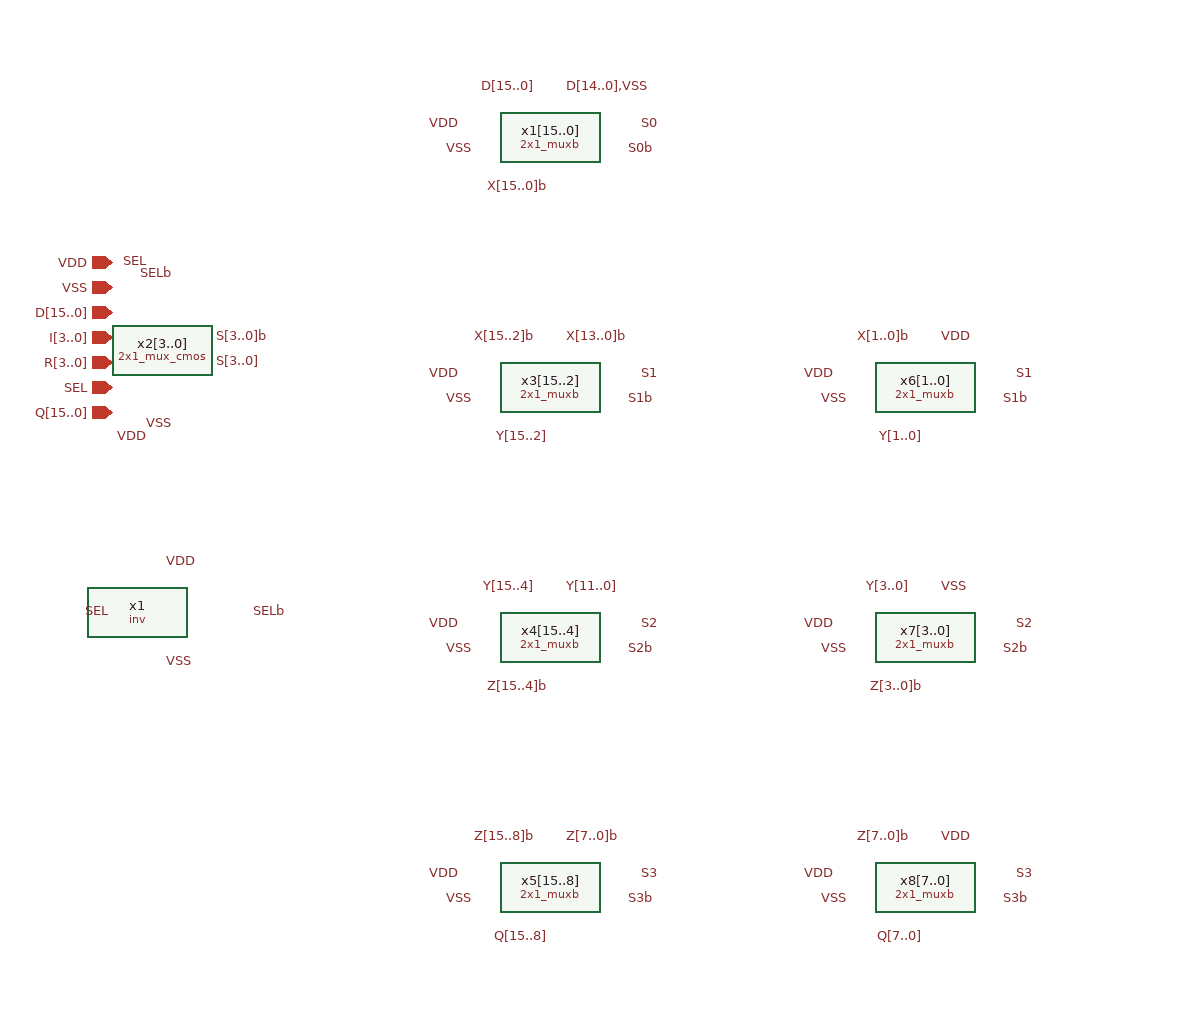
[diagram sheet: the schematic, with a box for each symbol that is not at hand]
v {xschem version=3.4.7 file_version=1.2}
G {}
K {}
V {}
S {}
E {}
C {engn1600-team1/CAD5/2x1_muxb.sym} 0 -300 3 1 {name=x1[15..0] kI=1 kYb=1 kY=1}
C {iopin.sym} -350 -200 2 0 {name=p1 lab=VDD}
C {iopin.sym} -350 -180 2 0 {name=p2 lab=VSS}
C {lab_pin.sym} -10 -340 2 1 {name=p3 lab=D[15..0]}
C {lab_pin.sym} 70 -310 0 1 {name=p4 lab=S0}
C {lab_pin.sym} 60 -290 0 1 {name=p5 lab=S0b}
C {lab_pin.sym} -70 -310 2 1 {name=p7 lab=VDD}
C {lab_pin.sym} -60 -290 0 0 {name=p8 lab=VSS}
C {lab_pin.sym} 10 -340 0 1 {name=p9 lab=D[14..0],VSS}
C {ipin.sym} -350 -160 0 0 {name=p11 lab=D[15..0]}
C {opin.sym} -350 -80 0 1 {name=p6 lab=Q[15..0]}
C {ipin.sym} -350 -120 0 0 {name=p10 lab=R[3..0]}
C {ipin.sym} -350 -140 0 0 {name=p12 lab=I[3..0]}
C {ipin.sym} -350 -100 0 0 {name=p13 lab=SEL}
C {engn1600-team1/CAD5/2x1_mux_cmos.sym} -310 -130 2 1 {name=x2[3..0] kI=1 kYb=1 kY=1}
C {lab_pin.sym} -320 -200 1 0 {name=p14 lab=SEL}
C {lab_pin.sym} -300 -190 1 0 {name=p15 lab=SELb}
C {lab_pin.sym} -320 -60 3 0 {name=p17 lab=VDD}
C {lab_pin.sym} -300 -70 1 1 {name=p18 lab=VSS}
C {lab_pin.sym} -270 -120 0 1 {name=p16 lab=S[3..0]}
C {lab_pin.sym} -270 -140 0 1 {name=p19 lab=S[3..0]b}
C {engn1600-team1/CAD5/inv.sym} -330 80 0 0 {name=x1}
C {lab_pin.sym} -350 80 0 0 {name=p20 lab=SEL}
C {lab_pin.sym} -240 80 2 0 {name=p21 lab=SELb}
C {lab_pin.sym} -310 40 0 1 {name=p22 lab=VDD}
C {lab_pin.sym} -310 120 0 1 {name=p23 lab=VSS}
C {lab_pin.sym} 0 -260 3 0 {name=p24 lab=X[15..0]b}
C {engn1600-team1/CAD5/2x1_muxb.sym} 0 -100 3 1 {name=x3[15..2] kI=1 kYb=1 kY=1}
C {lab_pin.sym} 70 -110 0 1 {name=p26 lab=S1}
C {lab_pin.sym} 60 -90 0 1 {name=p27 lab=S1b}
C {lab_pin.sym} -70 -110 2 1 {name=p28 lab=VDD}
C {lab_pin.sym} -60 -90 0 0 {name=p29 lab=VSS}
C {lab_pin.sym} 10 -140 0 1 {name=p30 lab=X[13..0]b}
C {engn1600-team1/CAD5/2x1_muxb.sym} 0 100 3 1 {name=x4[15..4] kI=1 kYb=1 kY=1}
C {lab_pin.sym} -10 60 2 1 {name=p25 lab=Y[15..4]}
C {lab_pin.sym} 70 90 0 1 {name=p32 lab=S2}
C {lab_pin.sym} 60 110 0 1 {name=p33 lab=S2b}
C {lab_pin.sym} -70 90 2 1 {name=p34 lab=VDD}
C {lab_pin.sym} -60 110 0 0 {name=p35 lab=VSS}
C {lab_pin.sym} 10 60 0 1 {name=p36 lab=Y[11..0]}
C {lab_pin.sym} 0 140 3 0 {name=p37 lab=Z[15..4]b}
C {engn1600-team1/CAD5/2x1_muxb.sym} 0 300 3 1 {name=x5[15..8] kI=1 kYb=1 kY=1}
C {lab_pin.sym} 70 290 0 1 {name=p38 lab=S3}
C {lab_pin.sym} 60 310 0 1 {name=p39 lab=S3b}
C {lab_pin.sym} -70 290 2 1 {name=p40 lab=VDD}
C {lab_pin.sym} -60 310 0 0 {name=p41 lab=VSS}
C {lab_pin.sym} 10 260 0 1 {name=p42 lab=Z[7..0]b}
C {lab_pin.sym} 0 340 3 0 {name=p43 lab=Q[15..8]}
C {lab_pin.sym} 290 -140 0 0 {name=p31 lab=X[1..0]b}
C {engn1600-team1/CAD5/2x1_muxb.sym} 300 -100 3 1 {name=x6[1..0] kI=1 kYb=1 kY=1}
C {lab_pin.sym} 370 -110 0 1 {name=p44 lab=S1}
C {lab_pin.sym} 360 -90 0 1 {name=p45 lab=S1b}
C {lab_pin.sym} 230 -110 2 1 {name=p46 lab=VDD}
C {lab_pin.sym} 240 -90 0 0 {name=p47 lab=VSS}
C {lab_pin.sym} 310 -140 0 1 {name=p48 lab=VDD}
C {engn1600-team1/CAD5/2x1_muxb.sym} 300 100 3 1 {name=x7[3..0] kI=1 kYb=1 kY=1}
C {lab_pin.sym} 290 60 2 1 {name=p49 lab=Y[3..0]}
C {lab_pin.sym} 370 90 0 1 {name=p50 lab=S2}
C {lab_pin.sym} 360 110 0 1 {name=p51 lab=S2b}
C {lab_pin.sym} 230 90 2 1 {name=p52 lab=VDD}
C {lab_pin.sym} 240 110 0 0 {name=p53 lab=VSS}
C {lab_pin.sym} 310 60 0 1 {name=p54 lab=VSS}
C {lab_pin.sym} 290 260 0 0 {name=p55 lab=Z[7..0]b}
C {engn1600-team1/CAD5/2x1_muxb.sym} 300 300 3 1 {name=x8[7..0] kI=1 kYb=1 kY=1}
C {lab_pin.sym} 370 290 0 1 {name=p56 lab=S3}
C {lab_pin.sym} 360 310 0 1 {name=p57 lab=S3b}
C {lab_pin.sym} 230 290 2 1 {name=p58 lab=VDD}
C {lab_pin.sym} 240 310 0 0 {name=p59 lab=VSS}
C {lab_pin.sym} 310 260 0 1 {name=p60 lab=VDD}
C {lab_pin.sym} 300 340 3 0 {name=p61 lab=Q[7..0]}
C {lab_pin.sym} -10 -140 0 0 {name=p62 lab=X[15..2]b}
C {lab_pin.sym} 0 -60 3 0 {name=p63 lab=Y[15..2]}
C {lab_pin.sym} 300 -60 3 0 {name=p64 lab=Y[1..0]}
C {lab_pin.sym} 300 140 3 0 {name=p65 lab=Z[3..0]b}
C {lab_pin.sym} -10 260 2 1 {name=p66 lab=Z[15..8]b}
